SITE unithd
  SIZE 1 BY 1 ;
END unithd
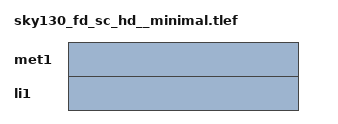
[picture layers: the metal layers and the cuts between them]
LAYER li1
  TYPE ROUTING ;
END li1
LAYER met1
  TYPE ROUTING ;
END met1
